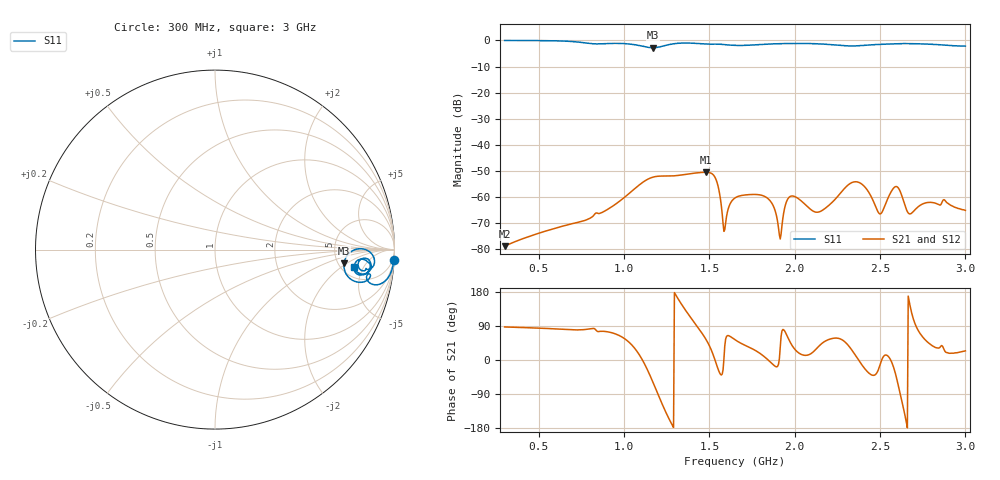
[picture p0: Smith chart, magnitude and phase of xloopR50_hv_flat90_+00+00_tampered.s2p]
! xloopR50_hv_flat90_+00+00_tampered, gap C 0.80 pF
! simulated by sim/fixtures_fdtd.py (S12 = S21, S22 not computed)
# HZ S RI R 50
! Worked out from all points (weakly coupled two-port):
!   541 points, 300 MHz to 3 GHz, reference 50 ohm
!   highest |S21| = -50.52 dB at 1.48 GHz (marker M1); lowest = -78.8 dB at 300 MHz (marker M2)
!   lowest |S11| = -2.8 dB at 1.17 GHz (marker M3), VSWR 6.22, Z = 281 - j90.1 ohm
!   |S11| at or under -10 dB: nowhere
!   |S22| runs from - to - dB; largest |S21 - S12| = 0
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3e8  0.9964 -0.0607  5.6e-06 0.000114  5.6e-06 0.000114  0 0
7.5e8  0.8934 -0.1963  6.09e-05 0.000334  6.09e-05 0.000334  0 0
1.17e9  0.7191 -0.0764  0.00122 -0.00207  0.00122 -0.00207  0 0
1.2e9  0.741 -0.0272  -7.6e-05 -0.0025  -7.6e-05 -0.0025  0 0
1.48e9  0.8469 -0.1101  0.00174 0.00242  0.00174 0.00242  0 0
1.54e9  0.8423 -0.1073  0.00208 -0.000357  0.00208 -0.000357  0 0
1.585e9  0.8236 -0.1182  0.000219 7.2e-06  0.000219 7.2e-06  0 0
1.65e9  0.7986 -0.0941  0.000571 0.000771  0.000571 0.000771  0 0
1.84e9  0.8469 -0.0503  0.00095 2.91e-05  0.00095 2.91e-05  0 0
1.88e9  0.8584 -0.0581  0.000591 -0.000156  0.000591 -0.000156  0 0
1.915e9  0.8643 -0.0676  0.000132 8.46e-05  0.000132 8.46e-05  0 0
1.945e9  0.8662 -0.0749  0.000199 0.000667  0.000199 0.000667  0 0
1.97e9  0.8682 -0.08  0.00065 0.00077  0.00065 0.00077  0 0
2.1e9  0.8608 -0.1194  0.000528 0.000175  0.000528 0.000175  0 0
2.35e9  0.7797 -0.0785  0.00188 0.000547  0.00188 0.000547  0 0
2.415e9  0.8066 -0.0543  0.00136 -0.000645  0.00136 -0.000645  0 0
2.495e9  0.8371 -0.0582  0.000455 -0.00016  0.000455 -0.00016  0 0
2.55e9  0.8501 -0.0673  0.000998 0.00015  0.000998 0.00015  0 0
2.6e9  0.8629 -0.0794  0.000924 -0.00127  0.000924 -0.00127  0 0
2.675e9  0.8609 -0.1088  -0.000387 0.000273  -0.000387 0.000273  0 0
2.875e9  0.8031 -0.1414  0.000789 0.000413  0.000789 0.000413  0 0
3e9  0.7721 -0.0966  0.000506 0.000227  0.000506 0.000227  0 0
